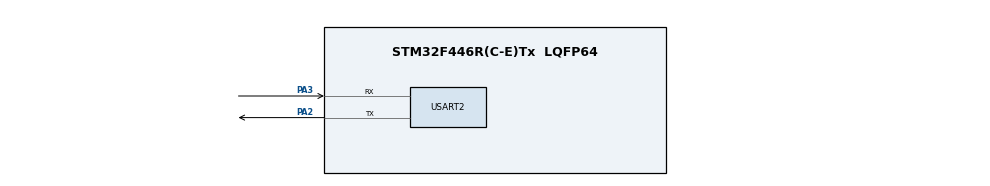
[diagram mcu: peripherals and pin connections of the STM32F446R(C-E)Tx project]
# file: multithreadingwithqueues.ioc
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FREERTOS.Tasks01=defaultTask,0,128,StartDefaultTask,Default,NULL,Dynamic,NULL,NULL
FREERTOS.configUSE_COUNTING_SEMAPHORES=1
FREERTOS.configUSE_NEWLIB_REENTRANT=1
Mcu.Family=STM32F4
Mcu.Name=STM32F446R(C-E)Tx
Mcu.Package=LQFP64
NVIC.PriorityGroup=NVIC_PRIORITYGROUP_4
NVIC.TIM1_UP_TIM10_IRQn=true\:15\:0\:false\:false\:true\:false\:false\:true\:true
NVIC.TimeBase=TIM1_UP_TIM10_IRQn
NVIC.TimeBaseIP=TIM1
PA2.Mode=Asynchronous
PA2.Signal=USART2_TX
PA3.Mode=Asynchronous
PA3.Signal=USART2_RX
PH0-OSC_IN.Mode=HSE-External-Oscillator
PH0-OSC_IN.Signal=RCC_OSC_IN
PH1-OSC_OUT.Mode=HSE-External-Oscillator
PH1-OSC_OUT.Signal=RCC_OSC_OUT
ProjectManager.HeapSize=0x200
ProjectManager.StackSize=0x400
ProjectManager.TargetToolchain=STM32CubeIDE
RCC.AHBFreq_Value=180000000
RCC.APB1CLKDivider=RCC_HCLK_DIV4
RCC.APB1Freq_Value=45000000
RCC.APB1TimFreq_Value=90000000
RCC.APB2CLKDivider=RCC_HCLK_DIV2
RCC.APB2Freq_Value=90000000
RCC.APB2TimFreq_Value=180000000
RCC.CortexFreq_Value=180000000
RCC.HCLKFreq_Value=180000000
RCC.PLLM=8
RCC.PLLN=180
RCC.SYSCLKFreq_VALUE=180000000
RCC.SYSCLKSource=RCC_SYSCLKSOURCE_PLLCLK
RCC.USBFreq_Value=180000000
RCC.VCOOutputFreq_Value=360000000
USART2.VirtualMode=VM_ASYNC
VP_FREERTOS_VS_CMSIS_V1.Mode=CMSIS_V1
VP_SYS_VS_tim1.Mode=TIM1
board=custom

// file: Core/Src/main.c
#include "main.h"
#include "FreeRTOS.h"
#include "FreeRTOSconfig.h"
#include "task.h"
#include "semphr.h"
#include "string.h"
#include "stdio.h"

UART_HandleTypeDef huart2;

/* Semaphore Handle */
SemaphoreHandle_t xsemaphoreHandle;

/* Function Prototypes */
void SystemClock_Config(void);
static void MX_GPIO_Init(void);
static void MX_USART2_UART_Init(void);
void EventProcessingTask(void *pvParameters);
void SimulatedISR(void); // Simulating an interrupt in software
void UART_Send(char *message);

/* Main Function */
int main(void)
{

    HAL_Init();
    SystemClock_Config();
    MX_GPIO_Init();
    MX_USART2_UART_Init();

    /* Create a Counting Semaphore */
    xsemaphoreHandle = xSemaphoreCreateCounting(5, 0); // Max count = 5, Initial count = 0

    if (xsemaphoreHandle == NULL)
    {
        UART_Send("Semaphore creation failed!\r\n");
        while(1);
    }

    xTaskCreate(EventProcessingTask, "EventTask", 128, NULL, 2, NULL);

    vTaskStartScheduler();

    while (1);
}

/* Event Processing Task */
void EventProcessingTask(void *pvParameters)
{
    while (1)
    {
        /* Wait for an event (ISR signal) */
        if (xSemaphoreTake(xsemaphoreHandle, portMAX_DELAY) == pdPASS)
        {
            UART_Send("Event Received. Processing...\r\n");
            vTaskDelay(2000); // Simulate event processing time
            UART_Send("Event Processing Done!\r\n");
        }
    }
}

/* Simulated ISR - Simulating an Interrupt */
void SimulatedISR(void)
{
    BaseType_t xHigherPriorityTaskWoken = pdFALSE;

    /* 'Give' the counting semaphore from ISR */
    xSemaphoreGiveFromISR(xsemaphoreHandle, &xHigherPriorityTaskWoken);
    xSemaphoreGiveFromISR(xsemaphoreHandle, &xHigherPriorityTaskWoken);
    xSemaphoreGiveFromISR(xsemaphoreHandle, &xHigherPriorityTaskWoken);

    /* Force a context switch if needed */
    portYIELD_FROM_ISR(xHigherPriorityTaskWoken);
}

/* UART Send Helper Function */
void UART_Send(char *message)
{
    HAL_UART_Transmit(&huart2, (uint8_t *)message, strlen(message), HAL_MAX_DELAY);
}

void SystemClock_Config(void)
{
  RCC_OscInitTypeDef RCC_OscInitStruct = {0};
  RCC_ClkInitTypeDef RCC_ClkInitStruct = {0};

  /** Configure the main internal regulator output voltage
  */
  __HAL_RCC_PWR_CLK_ENABLE();
  __HAL_PWR_VOLTAGESCALING_CONFIG(PWR_REGULATOR_VOLTAGE_SCALE1);

  /** Initializes the RCC Oscillators according to the specified parameters
  * in the RCC_OscInitTypeDef structure.
  */
  RCC_OscInitStruct.OscillatorType = RCC_OSCILLATORTYPE_HSE;
  RCC_OscInitStruct.HSEState = RCC_HSE_ON;
  RCC_OscInitStruct.PLL.PLLState = RCC_PLL_ON;
  RCC_OscInitStruct.PLL.PLLSource = RCC_PLLSOURCE_HSE;
  RCC_OscInitStruct.PLL.PLLM = 4;
  RCC_OscInitStruct.PLL.PLLN = 180;
  RCC_OscInitStruct.PLL.PLLP = RCC_PLLP_DIV2;
  RCC_OscInitStruct.PLL.PLLQ = 2;
  RCC_OscInitStruct.PLL.PLLR = 2;
  if (HAL_RCC_OscConfig(&RCC_OscInitStruct) != HAL_OK)
  {
    Error_Handler();
  }

  /** Activate the Over-Drive mode
  */
  if (HAL_PWREx_EnableOverDrive() != HAL_OK)
  {
    Error_Handler();
  }

  /** Initializes the CPU, AHB and APB buses clocks
  */
  RCC_ClkInitStruct.ClockType = RCC_CLOCKTYPE_HCLK|RCC_CLOCKTYPE_SYSCLK
                              |RCC_CLOCKTYPE_PCLK1|RCC_CLOCKTYPE_PCLK2;
  RCC_ClkInitStruct.SYSCLKSource = RCC_SYSCLKSOURCE_PLLCLK;
  RCC_ClkInitStruct.AHBCLKDivider = RCC_SYSCLK_DIV1;
  RCC_ClkInitStruct.APB1CLKDivider = RCC_HCLK_DIV4;
  RCC_ClkInitStruct.APB2CLKDivider = RCC_HCLK_DIV2;

  if (HAL_RCC_ClockConfig(&RCC_ClkInitStruct, FLASH_LATENCY_5) != HAL_OK)
  {
    Error_Handler();
  }
}

static void MX_USART2_UART_Init(void)
{

  huart2.Instance = USART2;
  huart2.Init.BaudRate = 115200;
  huart2.Init.WordLength = UART_WORDLENGTH_8B;
  huart2.Init.StopBits = UART_STOPBITS_1;
  huart2.Init.Parity = UART_PARITY_NONE;
  huart2.Init.Mode = UART_MODE_TX_RX;
  huart2.Init.HwFlowCtl = UART_HWCONTROL_NONE;
  huart2.Init.OverSampling = UART_OVERSAMPLING_16;
  if (HAL_UART_Init(&huart2) != HAL_OK)
  {
    Error_Handler();
  }

}

static void MX_GPIO_Init(void)
{

  /* GPIO Ports Clock Enable */
  __HAL_RCC_GPIOH_CLK_ENABLE();
  __HAL_RCC_GPIOA_CLK_ENABLE();

}

void HAL_TIM_PeriodElapsedCallback(TIM_HandleTypeDef *htim)
{
  if (htim->Instance == TIM1) {
    HAL_IncTick();
  }
}

void Error_Handler(void)
{
  __disable_irq();
  while (1)
  {
  }
}
